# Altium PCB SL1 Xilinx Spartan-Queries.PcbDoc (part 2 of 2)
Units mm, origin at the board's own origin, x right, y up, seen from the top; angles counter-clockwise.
Board outline 180.01 x 50.51 mm, 2 copper layers (Top Layer, Bottom Layer), stack 1.646 mm thick; 115 components, 126 nets, 642 pads, 244 vias.
Unrouted connection lines stored in the file: 1.

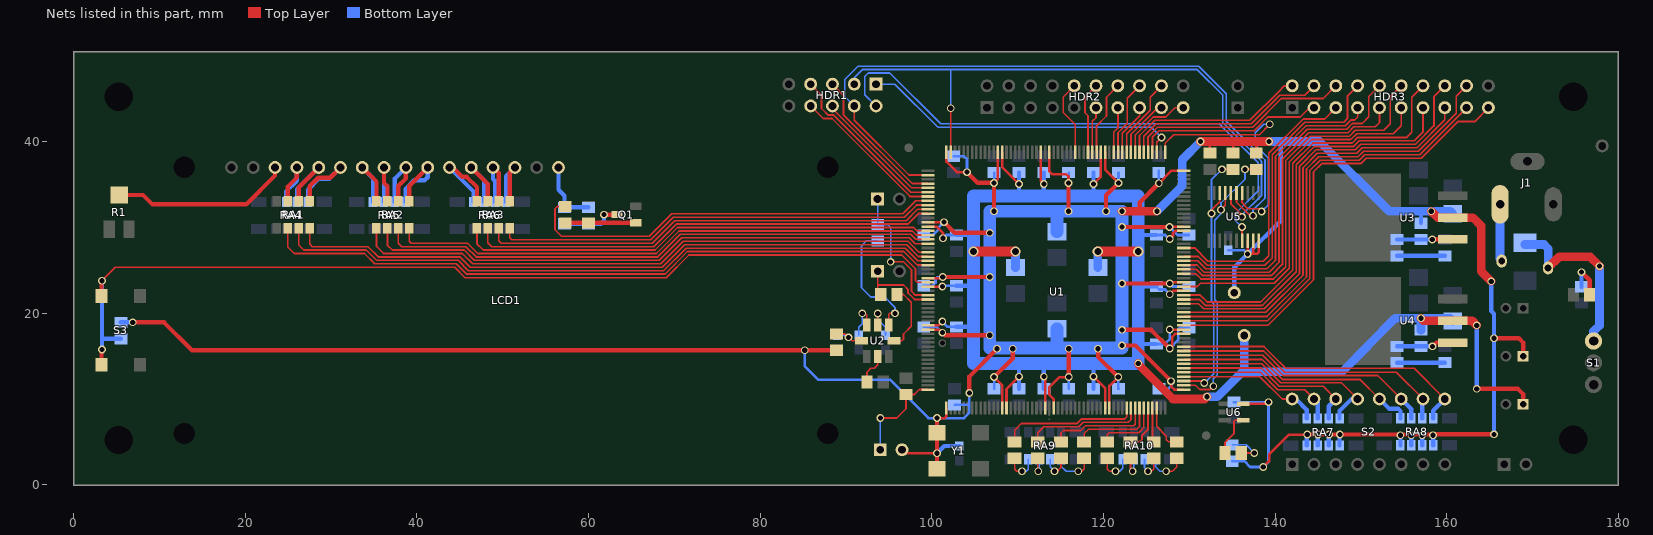
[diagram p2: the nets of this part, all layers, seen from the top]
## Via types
v1: diameter 0.9, hole 0.6, Top Layer to Bottom Layer, tented both sides, 168 vias
v2: diameter 1.5, hole 0.8, Top Layer to Bottom Layer, tented both sides, 46 vias
v3: diameter 1.2, hole 0.8, Top Layer to Bottom Layer, 18 vias
v4: diameter 1.2, hole 0.8, Top Layer to Bottom Layer, tented both sides, 11 vias
v5: diameter 0.9, hole 0.6, Top Layer to Bottom Layer, 1 vias

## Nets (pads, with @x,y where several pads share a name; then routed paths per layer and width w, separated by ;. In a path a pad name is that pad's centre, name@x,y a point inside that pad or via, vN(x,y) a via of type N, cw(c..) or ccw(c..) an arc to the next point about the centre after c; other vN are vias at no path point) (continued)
HA10: HDR2.10 U1.178 | length 8.8
  Top Layer w0.2: HDR2.10@116.6,46.5 115.3,45.2 115.3,43.4 116.7,42 U1.178@116.7,38.775
HA11: HDR2.11 U1.174 | length 5.4
  Top Layer w0.2: U1.174@118.7,38.775 118.7,42.375 119.14,42.815 HDR2.11@119.14,43.96
HA12: HDR2.12 U1.175 | length 8.4
  Top Layer w0.2: U1.175@118.2,38.775 118.2,43.025 117.85,43.375 117.85,45.21 HDR2.12@119.14,46.5
HA13: HDR2.13 U1.169 | length 5.4
  Top Layer w0.2: U1.169@121.2,38.775 121.2,41.122 121.68,41.602 HDR2.13@121.68,43.96
HA14: HDR2.14 U1.173 | length 8.8
  Top Layer w0.2: U1.173@119.2,38.775 119.2,41.85 120.35,43 120.35,45.17 HDR2.14@121.68,46.5
HA15: HDR2.15 U1.167 | length 6
  Top Layer w0.2: U1.167@122.2,38.775 122.2,40.991 124.22,43.011 HDR2.15@124.22,43.96
HA16: HDR2.16 U1.168 | length 8.8
  Top Layer w0.2: U1.168@121.7,38.775 121.7,41.056 122.775,42.131 122.775,45.055 HDR2.16@124.22,46.5
HA17: HDR2.17 U1.165 | length 6.9
  Top Layer w0.2: U1.165@123.2,38.775 123.2,40.85 126.31,43.96 HDR2.17@126.76,43.96
HA18: HDR2.18 U1.166 | length 9.4
  Top Layer w0.2: U1.166@122.7,38.775 122.7,40.925 125.45,43.675 125.45,45.19 HDR2.18@126.76,46.5
HA19: HDR2.19 U1.164 | length 8.9
  Top Layer w0.2: U1.164@123.7,38.775 123.7,40.784 125.801,42.885 127.26,42.885 128.335,43.96 HDR2.19@129.3,43.96
HARD_TCK: HDR1.3 U1.207 U5.6 | length 75.3
  Top Layer w0.2: U1.207@102.2,38.775 v1(102.2,43.9) ; U5.6@134.85,34 134.85,32.769 136.144,31.475 v1(136.144,31.242)
  Bottom Layer w0.2: HDR1.3@90.96,46.7 90.96,47.46 91.9,48.4 130.934,48.4 133.9,45.434 133.9,42.225 ; v1(102.2,43.9) 102.2,48.4 ; 133.9,42.234 134.125,42.009 134.125,42 138.425,37.7 138.425,33.777 136.144,31.496 v1(136.144,31.242)
HARD_TDI: HDR1.1 U1.159 | length 37.8
  Top Layer w0.2: U1.159@126.2,38.775 126.2,39.95 v1(126.75,40.5)
  Bottom Layer w0.2: HDR1.1@93.5,46.7 95.7,46.7 100.725,41.675 125.575,41.675 v1(126.75,40.5)
HARD_TDO: HDR1.2 U5.17 | length 64.8
  Top Layer w0.2: U5.17@136.15,28.45 v1(136.15,30.05)
  Bottom Layer w0.2: HDR1.2@93.5,44.16 92.2,45.46 92.2,47.6 92.6,48 95.1,48 101.025,42.075 133.484,42.075 134.723,40.837 138.025,37.534 138.025,34.266 135.39,31.631 135.39,30.81 v1(136.15,30.05)
HARD_TMS: HDR1.4 U1.2 U5.5 | length 83.2
  Top Layer w0.2: HDR1.4@90.96,44.16 90.96,42.5 97.335,36.125 U1.2@99.55,36.125 ; U5.5@135.5,34 135.5,32.95 137.081,31.369 v1(137.414,31.369)
  Bottom Layer w0.2: HDR1.4@90.96,44.16 89.85,45.27 89.85,47.25 91.405,48.805 131.095,48.805 134.3,45.6 134.3,42.4 138.825,37.875 138.825,33.415 137.414,32.004 v1(137.414,31.369)
HB2: HDR3.2 U1.163 | length 22.1
  Top Layer w0.2: U1.163@124.2,38.775 124.2,40.719 125.967,42.485 137.054,42.485 140.402,45.833 141.069,46.5 HDR3.2@142,46.5
HB3: HDR3.3 U1.160 | length 22
  Top Layer w0.2: U1.160@125.7,38.775 125.7,40.522 126.464,41.285 137.551,41.285 139.149,42.883 142.933,42.883 144.01,43.96 HDR3.3@144.54,43.96
HB4: HDR3.4 U1.162 | length 24.1
  Top Layer w0.2: U1.162@124.7,38.775 124.7,40.653 126.132,42.085 137.22,42.085 140.559,45.425 143.465,45.425 HDR3.4@144.54,46.5
HB5: HDR3.5 U1.138 | length 32.8
  Top Layer w0.2: U1.138@129.35,27.625 130.616,27.625 132.162,26.079 138.629,26.079 139.25,26.7 139.25,38.634 143.266,42.65 145.77,42.65 HDR3.5@147.08,43.96
HB6: HDR3.6 U1.161 | length 26.1
  Top Layer w0.2: U1.161@125.2,38.775 125.2,40.587 126.298,41.685 137.385,41.685 140.725,45.025 145.605,45.025 HDR3.6@147.08,46.5
HB7: HDR3.7 U1.135 | length 36.2
  Top Layer w0.2: U1.135@129.35,26.125 130.984,26.125 131.909,25.2 139.05,25.2 140.05,26.2 140.05,38.303 143.597,41.85 148.166,41.85 148.825,42.509 148.825,42.525 149.275,42.525 149.62,42.87 HDR3.7@149.62,43.96
HB8: HDR3.8 U1.136 | length 37.9
  Top Layer w0.2: U1.136@129.35,26.625 131.05,26.625 132.075,25.6 138.8,25.6 139.65,26.45 139.65,38.469 143.431,42.25 148,42.25 148.425,42.675 148.425,45.305 HDR3.8@149.62,46.5
HB9: HDR3.9 U1.133 | length 39.4
  Top Layer w0.2: U1.133@129.35,25.125 130.825,25.125 131.55,24.4 139.55,24.4 140.85,25.7 140.85,34.825 140.85,37.972 143.928,41.05 148.497,41.05 149.172,41.725 151.675,41.725 152.16,42.21 HDR3.9@152.16,43.96
HB10: HDR3.10 U1.134 | length 40.7
  Top Layer w0.2: U1.134@129.35,25.625 130.891,25.625 131.716,24.8 139.3,24.8 140.45,25.95 140.45,38.137 143.763,41.45 148.331,41.45 149.006,42.125 150.15,42.125 150.925,42.9 150.925,45.265 HDR3.10@152.16,46.5
HB11: HDR3.11 U1.129 | length 42.5
  Top Layer w0.2: U1.129@129.35,23.125 130.925,23.125 131.305,23.505 139.905,23.505 141.65,25.25 141.65,35.4 141.65,37.64 144.26,40.25 148.828,40.25 149.503,40.925 153.75,40.925 154.7,41.875 HDR3.11@154.7,43.96
HB12: HDR3.12 U1.132 | length 44
  Top Layer w0.2: U1.132@129.35,24.625 130.75,24.625 131.375,24 139.8,24 141.25,25.45 141.25,37.806 144.094,40.65 148.663,40.65 149.338,41.325 152.675,41.325 153.425,42.075 153.425,45.225 HDR3.12@154.7,46.5
HB13: HDR3.13 U1.126 | length 46.7
  Top Layer w0.2: U1.126@129.35,21.625 131.175,21.625 131.875,20.925 138.525,20.925 142.45,24.85 142.45,35.175 142.45,37.309 144.591,39.45 149.16,39.45 149.81,40.1 156.197,40.1 157.24,41.143 HDR3.13@157.24,43.96
HB14: HDR3.14 U1.127 | length 48.3
  Top Layer w0.2: U1.127@129.35,22.125 131.275,22.125 132.075,21.325 138.325,21.325 142.05,25.05 142.05,35.2 142.05,37.475 144.425,39.85 148.994,39.85 149.644,40.5 155.325,40.5 155.925,41.1 155.925,45.185 HDR3.14@157.24,46.5
HB15: HDR3.15 U1.123 | length 48.5
  Top Layer w0.2: U1.123@129.35,20.125 138.925,20.125 143.25,24.45 143.25,36.977 144.923,38.65 149.491,38.65 150.141,39.3 156.529,39.3 159.78,42.551 HDR3.15@159.78,43.96
HB16: HDR3.16 U1.125 | length 50.7
  Top Layer w0.2: U1.125@129.35,21.125 131.075,21.125 131.675,20.525 138.725,20.525 142.85,24.65 142.85,34.7 142.85,37.143 144.757,39.05 149.325,39.05 149.975,39.7 156.363,39.7 158.5,41.837 158.5,45.22 HDR3.16@159.78,46.5
HB17: HDR3.17 U1.121 | length 50.6
  Top Layer w0.2: U1.121@129.35,19.125 139.109,19.125 144.05,24.066 144.05,36.646 145.254,37.85 149.823,37.85 150.448,38.475 156.835,38.475 HDR3.17@162.32,43.96
HB18: HDR3.18 U1.122 | length 52.6
  Top Layer w0.2: U1.122@129.35,19.625 139.044,19.625 143.65,24.231 143.65,36.812 145.088,38.25 149.657,38.25 150.307,38.9 156.694,38.9 161.1,43.306 161.1,45.28 HDR3.18@162.32,46.5
HB19: HDR3.19 U1.120 | length 53.4
  Top Layer w0.2: U1.120@129.35,18.625 139.175,18.625 144.475,23.925 144.475,36.505 145.42,37.45 149.988,37.45 150.613,38.075 157.025,38.075 161.291,42.341 163.241,42.341 HDR3.19@164.86,43.96
I\N\I\T\: R5.2 U1.107 U5.8 | length 32.6
  Top Layer w0.2: U1.107@129.35,12.125 131.5,12.125 v1(131.75,11.875) ; v1(132.575,31.625) 132.575,32.025 133.55,33 U5.8@133.55,34 ; v1(133.803,36.78) R5.2@135.1,36.775
  Bottom Layer w0.2: v1(131.75,11.875) 132.85,12.975 132.85,21.132 132.575,21.407 132.575,35.552 v1(133.803,36.78)
JTAG_NEXUS_TCK: HDR1.7 U1.6 | length 19.8
  Top Layer w0.2: HDR1.7@85.88,46.7 87.15,45.43 87.15,43.875 87.925,43.1 88.575,43.1 97.55,34.125 U1.6@99.55,34.125
JTAG_NEXUS_TDI: HDR1.5 U1.4 | length 17.3
  Top Layer w0.2: HDR1.5@88.42,46.7 89.7,45.42 89.7,43.15 97.725,35.125 U1.4@99.55,35.125
JTAG_NEXUS_TDO: HDR1.6 U1.5 | length 15.3
  Top Layer w0.2: HDR1.6@88.42,44.16 88.42,43.83 97.625,34.625 U1.5@99.55,34.625
JTAG_NEXUS_TMS: HDR1.8 U1.7 | length 18
  Top Layer w0.2: HDR1.8@85.88,44.16 87.34,42.7 88.375,42.7 97.45,33.625 U1.7@99.55,33.625
LCD_CONTRAST: LCD1.3 R1.W | length 21
  Top Layer w0.5: R1.W@5.3,33.8 8.1,33.8 9.2,32.7 20.113,32.7 23.48,36.067 LCD1.3@23.48,37
LCD_DB0: RA2.5 U1.20 | length 68.8
  Top Layer w0.2: RA2.5@35.295,29.925 35.295,27.8 36.12,26.975 45.3,26.975 46.5,25.775 68.41,25.775 71.035,28.4 97.225,28.4 98.5,27.125 U1.20@99.55,27.125
LCD_DB1: RA2.6 U1.18 | length 67.1
  Top Layer w0.2: RA2.6@36.565,29.925 36.565,27.935 37.125,27.375 45.5,27.375 46.7,26.175 68.244,26.175 70.869,28.8 97.391,28.8 98.066,28.125 U1.18@99.55,28.125
LCD_DB2: RA2.7 U1.17 | length 65.5
  Top Layer w0.2: RA2.7@37.835,29.925 37.835,28.165 38.225,27.775 45.7,27.775 46.9,26.575 68.078,26.575 70.703,29.2 97.556,29.2 98.131,28.625 U1.17@99.55,28.625
LCD_DB3: RA2.8 U1.16 | length 63.8
  Top Layer w0.2: RA2.8@39.105,29.925 39.105,28.395 39.325,28.175 45.9,28.175 47.1,26.975 67.913,26.975 70.538,29.6 97.722,29.6 98.197,29.125 U1.16@99.55,29.125
LCD_DB4: RA3.5 U1.15 | length 55.9
  Top Layer w0.2: RA3.5@46.995,29.925 46.995,28.105 47.725,27.375 67.747,27.375 70.372,30 97.888,30 98.263,29.625 U1.15@99.55,29.625
LCD_DB5: RA3.6 U1.11 | length 54.8
  Top Layer w0.2: RA3.6@48.265,29.925 48.265,28.235 48.725,27.775 67.581,27.775 70.206,30.4 97.197,30.4 98.422,31.625 U1.11@99.55,31.625
LCD_DB6: RA3.7 U1.10 | length 53.2
  Top Layer w0.2: RA3.7@49.535,29.925 49.535,28.465 49.825,28.175 67.416,28.175 70.041,30.8 97,30.8 98.325,32.125 U1.10@99.55,32.125
LCD_DB7: RA3.8 U1.9 | length 51.6
  Top Layer w0.2: RA3.8@50.805,29.925 50.805,28.82 51.05,28.575 67.25,28.575 69.875,31.2 96.8,31.2 98.225,32.625 U1.9@99.55,32.625
LCD_DB#0: LCD1.7 RA2.4 RA5.5 | length 9.2
  Top Layer w0.5: LCD1.7@33.64,37 35.295,35.345 RA2.4@35.295,33.075
  Bottom Layer w0.5: LCD1.7@33.64,37 34.895,35.745 RA5.5@34.895,32.975
LCD_DB#1: LCD1.8 RA2.3 RA5.6 | length 8.1
  Top Layer w0.5: LCD1.8@36.18,37 36.18,35.2 36.565,34.815 RA2.3@36.565,33.075
  Bottom Layer w0.5: RA5.6@36.165,32.975 36.165,36.985 LCD1.8@36.18,37
LCD_DB#2: LCD1.9 RA2.2 RA5.7 | length 8.8
  Top Layer w0.5: RA2.2@37.835,33.075 37.835,34.825 38.72,35.71 LCD1.9@38.72,37
  Bottom Layer w0.5: RA5.7@37.435,32.975 37.435,35.715 LCD1.9@38.72,37
LCD_DB#3: LCD1.10 RA2.1 RA5.8 | length 10.6
  Top Layer w0.5: RA2.1@39.105,33.075 39.105,34.845 LCD1.10@41.26,37
  Bottom Layer w0.5: RA5.8@38.705,32.975 38.705,34.505 39.7,35.5 40.9,35.5 41.26,35.86 LCD1.10@41.26,37
LCD_DB#4: LCD1.11 RA3.4 RA6.5 | length 11
  Top Layer w0.5: LCD1.11@43.8,37 44.2,37 45.297,35.903 45.797,35.903 46.995,34.705 RA3.4@46.995,33.075
  Bottom Layer w0.5: LCD1.11@43.8,37 46.595,34.205 RA6.5@46.595,32.975
LCD_DB#5: LCD1.12 RA3.3 RA6.6 | length 9.4
  Top Layer w0.5: LCD1.12@46.34,37 48.265,35.075 RA3.3@48.265,33.075
  Bottom Layer w0.5: LCD1.12@46.34,37 47.865,35.475 RA6.6@47.865,32.975
LCD_DB#6: LCD1.13 RA3.2 RA6.7 | length 8.3
  Top Layer w0.5: LCD1.13@48.88,37 49.535,36.345 RA3.2@49.535,33.075
  Bottom Layer w0.5: LCD1.13@48.88,37 48.88,35.655 49.135,35.4 RA6.7@49.135,32.975
LCD_DB#7: LCD1.14 RA3.1 RA6.8 | length 8.6
  Top Layer w0.5: RA3.1@50.805,33.075 50.805,36.385 LCD1.14@51.42,37
  Bottom Layer w0.5: RA6.8@50.405,32.975 50.405,35.985 LCD1.14@51.42,37
LCD_E: RA1.8 U1.21 | length 76.7
  Top Layer w0.2: RA1.8@27.505,29.925 27.505,28.095 27.825,27.775 34.3,27.775 35.5,26.575 45,26.575 46.2,25.375 68.575,25.375 71.2,28 97.059,28 98.434,26.625 U1.21@99.55,26.625
LCD_E#: LCD1.6 RA1.1 RA4.8 | length 12.5
  Top Layer w0.5: RA1.1@27.505,33.075 27.505,34.805 28.5,35.8 29.9,35.8 LCD1.6@31.1,37
  Bottom Layer w0.5: RA4.8@27.305,32.975 27.305,34.405 28.595,35.695 29.795,35.695 LCD1.6@31.1,37
LCD_LIGHT: R2.1 U1.8 | length 49.2
  Top Layer w0.2: R2.1@57.3,32.45 56.375,32.45 56.1,32.175 56.1,29.725 56.85,28.975 67.084,28.975 69.709,31.6 96.6,31.6 98.125,33.125 U1.8@99.55,33.125
LCD_RS: RA1.6 U1.23 | length 79.8
  Top Layer w0.2: RA1.6@24.965,29.925 24.965,27.735 25.725,26.975 33.9,26.975 35.1,25.775 44.6,25.775 45.8,24.575 68.907,24.575 71.532,27.2 96.725,27.2 98.3,25.625 U1.23@99.55,25.625
LCD_RS#: LCD1.4 RA1.3 RA4.6 | length 8.9
  Top Layer w0.5: RA1.3@24.965,33.075 24.965,34.79 26.02,35.845 LCD1.4@26.02,37
  Bottom Layer w0.5: RA4.6@24.765,32.975 24.765,34.195 26.02,35.45 LCD1.4@26.02,37
LCD_RW: RA1.7 U1.22 | length 78.2
  Top Layer w0.2: RA1.7@26.235,29.925 26.235,27.965 26.825,27.375 34.1,27.375 35.3,26.175 44.8,26.175 46,24.975 68.741,24.975 71.366,27.6 96.894,27.6 98.369,26.125 U1.22@99.55,26.125
LCD_RW#: LCD1.5 RA1.2 RA4.7 | length 10
  Top Layer w0.5: RA1.2@26.235,33.075 26.235,34.675 LCD1.5@28.56,37
  Bottom Layer w0.5: RA4.7@26.035,32.975 26.035,34.475 LCD1.5@28.56,37
LEDS0: LED0.1 U1.102 | length 5.5
  Top Layer w0.2: U1.102@126.2,8.975 126.2,6.825 127.325,5.7 127.325,5.275 127.575,5.025 LED0.1@128.55,5.025
LEDS1: LED1.1 U1.101 | length 4
  Top Layer w0.2: U1.101@125.7,8.975 125.7,8.875 125.7,5.175 LED1.1@125.85,5.025
LEDS2: LED2.1 U1.100 | length 5.4
  Top Layer w0.2: LED2.1@123.15,5.025 124.175,5.025 124.5,5.35 124.5,5.775 125.2,6.475 U1.100@125.2,8.975
LEDS3: LED3.1 U1.99 | length 7.7
  Top Layer w0.2: LED3.1@120.45,5.025 120.45,5.875 120.675,6.1 124.1,6.1 124.7,6.7 U1.99@124.7,8.975
LEDS4: LED4.1 U1.98 | length 9.9
  Top Layer w0.2: LED4.1@117.75,5.025 117.75,6 118.25,6.5 123.9,6.5 124.2,6.8 U1.98@124.2,8.975
LEDS5: LED5.1 U1.97 | length 12
  Top Layer w0.2: LED5.1@115.05,5.025 115.05,6.05 115.35,6.35 117.35,6.35 117.9,6.9 123.525,6.9 123.7,7.075 U1.97@123.7,8.975
LEDS6: LED6.1 U1.96 | length 13.9
  Top Layer w0.2: LED6.1@112.35,5.025 112.35,6.075 113.05,6.775 117.125,6.775 117.65,7.3 122.9,7.3 123.2,7.6 U1.96@123.2,8.975
LEDS7: LED7.1 U1.95 | length 16.1
  Top Layer w0.2: LED7.1@109.65,5.025 109.65,6.375 110.45,7.175 116.959,7.175 117.484,7.7 122.475,7.7 122.7,7.925 U1.95@122.7,8.975
M0: JP5.1 R7.2 U1.52 | length 11.6
  Top Layer w0.2: v1(94,7.8) 95.9,7.8 96.989,8.889 96.989,10.555 97.98,10.555 98.55,11.125 U1.52@99.55,11.125
  Bottom Layer w0.2: JP5.1@94,4.1 v1(94,7.8)
NetC15_1: C15.1 R11.2 U2.8 | length 4.6
  Top Layer w0.2: R11.2@88.88,17.6 89.9,17.6 90.7,16.8 U2.8@91.8,16.8
  Bottom Layer w0.2: C15.1@89,17.45 89.78,17.45 v1(90.3,17.2)
NetC16_1: C16.1 U2.6 | length 4.2
  Top Layer w0.2: U2.6@93.697,18.663 93.702,18.668 v1(93.702,19.988)
  Bottom Layer w0.2: v1(93.702,19.988) 93.702,19.28 94.6,18.383 C16.1@94.6,17.45
NetC19_1: C19.1 U2.7 | length 4.5
  Top Layer w0.2: v1(91.9,20) 92.2,20 92.43,19.77 U2.7@92.43,18.65
  Bottom Layer w0.2: C19.1@91.5,17.45 91.5,18.392 91.9,18.792 v1(91.9,20)
NetD1_2: D1.2 F1.2 S1.3 | length 21.2
  Top Layer w1: F1.2@171.8,25.3 173.1,26.6 176.7,26.6 v1(177.8,25.5)
  Bottom Layer w1: D1.2@169.1,28.022 171.325,28.025 171.8,27.55 F1.2@171.8,25.3 ; S1.3@177.1,16.78 177.1,17.9 177.8,18.58 v1(177.8,25.5)
NetLCD1_16: LCD1.16 R8.1 R9.1 | length 7.7
  Bottom Layer w0.5: LCD1.16@56.5,37 56.5,34.4 57.2,33.7 57.2,32.35 R9.1@60,32.35
NetLED0_2: LED0.2 RA10.5 | length 5.5
  Top Layer w0.2: v1(127.3,1.6) 128.05,1.6 128.55,2.1 LED0.2@128.55,3.125
  Bottom Layer w0.2: RA10.5@126.055,3 126.055,2.125 126.58,1.6 ; 126.58,1.6 v1(127.3,1.6) 126.58,1.6
NetLED1_2: LED1.2 RA10.6 | length 3.6
  Top Layer w0.2: v1(125.2,1.6) 125.6,1.6 125.85,1.85 LED1.2@125.85,3.125
  Bottom Layer w0.2: RA10.6@124.785,3 124.785,2.015 v1(125.2,1.6)
NetLED2_2: LED2.2 RA10.7 | length 3.1
  Top Layer w0.2: LED2.2@123.15,3.125 123.15,1.85 v1(123.4,1.6)
  Bottom Layer w0.2: v1(123.4,1.6) 123.515,1.715 RA10.7@123.515,3
NetLED3_2: LED3.2 RA10.8 | length 4.4
  Top Layer w0.2: LED3.2@120.45,3.125 120.45,1.85 120.7,1.6 v1(121.4,1.6)
  Bottom Layer w0.2: v1(121.4,1.6) 121.9,1.6 122.245,1.945 RA10.8@122.245,3
NetLED4_2: LED4.2 RA9.5 | length 5.1
  Top Layer w0.2: v1(117.055,1.6) 117.45,1.6 117.75,1.9 LED4.2@117.75,3.125
  Bottom Layer w0.2: RA9.5@115.055,3 115.055,2.2 115.655,1.6 v1(117.055,1.6)
NetLED5_2: LED5.2 RA9.6 | length 3.6
  Top Layer w0.2: v1(114.3,1.6) 114.6,1.6 115.05,2.05 LED5.2@115.05,3.125
  Bottom Layer w0.2: RA9.6@113.785,3 113.785,2.115 v1(114.3,1.6)
NetLED6_2: LED6.2 RA9.7 | length 3
  Top Layer w0.2: LED6.2@112.35,3.125 112.35,1.65 v1(112.4,1.6)
  Bottom Layer w0.2: v1(112.4,1.6) 112.515,1.715 RA9.7@112.515,3
NetLED7_2: LED7.2 RA9.8 | length 4.2
  Top Layer w0.2: LED7.2@109.65,3.125 109.65,1.85 109.9,1.6 v1(110.5,1.6)
  Bottom Layer w0.2: v1(110.5,1.6) 111,1.6 111.245,1.845 RA9.8@111.245,3
NetLED8_1: LED8.1 R20.1 | length 4.5
  Top Layer w0.2: LED8.1@136.05,3.725 v1(137.575,3.725)
  Bottom Layer w0.2: R20.1@135,4.675 136.625,4.675 v1(137.575,3.725)
NetLED8_2: LED8.2 U6.4 | length 5.2
  Top Layer w0.2: LED8.2@134.15,3.725 134.15,4.925 135.2,5.975 135.2,7.4 135.35,7.55 U6.4@136.275,7.55
NetLED9_1: LED9.1 R15.1 | length 4.7
  Top Layer w0.5: v1(175.7,24.8) 176.65,23.85 LED9.1@176.65,22.15
  Bottom Layer w0.5: R15.1@175.7,23.1 v1(175.7,24.8)
NetQ1_1: Q1.1 R2.2 R3.2 | length 8.2
  Top Layer w0.5: R2.2@57.3,30.55 Q1.1@65.5,30.55
NetQ1_3: Q1.3 R8.2 R9.2 | length 6.9
  Top Layer w0.5: v1(61.8,31.5) Q1.3@63.3,31.5
  Bottom Layer w0.5: R8.2@57.2,30.45 61.45,30.45 61.8,30.8 v1(61.8,31.5)
NetR10_2: R10.2 U2.2 | length 3.7
  Top Layer w0.2: R10.2@92.45,12 92.45,13.15 92.9,13.6 93.28,13.6 93.7,14.02 U2.2@93.7,14.95
NetR12_1: R12.1 R13.2 U3.1 | length 6.5
  Top Layer w0.5: v1@158.32,28.62 U3.1@160.7,28.62
  Bottom Layer w0.5: R12.1@154.2,28.6 157,28.6 v1(158.3,28.6)
NetR12_2: R12.2 R14.2 | length 5.6
  Bottom Layer w0.5: R12.2@154.2,26.7 R14.2@159.8,26.7
NetR17_1: R17.1 R18.2 U4.1 | length 6.7
  Top Layer w0.5: v1(158.35,16.15) 158.8,16.6 U4.1@160.7,16.6
  Bottom Layer w0.5: R17.1@154.2,16.15 v1(158.35,16.15)
NetR17_2: R17.2 R19.1 | length 5.6
  Bottom Layer w0.5: R17.2@154.2,14.25 R19.1@159.8,14.25
PROG_B: R6.2 U1.106 U5.7 | length 34.3
  Top Layer w0.2: U1.106@129.35,11.625 130.725,11.625 131.225,11.125 132.425,11.125 v1(132.8,11.5) ; v1(133.7,32.075) 134.2,32.575 U5.7@134.2,34 ; v1(136.5,36.775) R6.2@137.8,36.775
  Bottom Layer w0.2: v1(132.8,11.5) 132.8,12.359 133.25,12.809 133.25,21.297 132.975,21.572 132.975,30.867 133.7,31.592 133.7,32.85 136.5,35.65 v1(136.5,36.775)
PWR_IN: F1.1 J1.1 | length 7.9
  Bottom Layer w1: J1.1@166.2,33.95 166.2,26.35 F1.1@166.4,26.1
SW0: RA7.1 S2.16 U1.108 | length 17.8
  Top Layer w0.2: U1.108@129.35,12.625 138.225,12.625 140.83,10.02 S2.16@142,10.02
  Bottom Layer w0.5: S2.16@142,10.02 142.43,10.02 143.695,8.755 143.695,7.755 143.7,7.75 143.7,8.63
SW1: RA7.2 S2.15 U1.109 | length 20.6
  Top Layer w0.2: U1.109@129.35,13.125 138.3,13.125 140.325,11.1 143.46,11.1 S2.15@144.54,10.02
  Bottom Layer w0.5: S2.15@144.54,10.02 144.97,9.59 RA7.2@144.97,7.75 ; RA7.2@144.965,7.875 S2.15@144.965,9.595
SW2: RA7.3 S2.14 U1.110 | length 21.8
  Top Layer w0.2: U1.110@129.35,13.625 138.375,13.625 140.5,11.5 145.6,11.5 S2.14@147.08,10.02
  Bottom Layer w0.5: RA7.3@146.24,7.75 146.24,9.18 S2.14@147.08,10.02
SW3: RA7.4 S2.13 U1.111 | length 25.5
  Top Layer w0.2: U1.111@129.35,14.125 138.441,14.125 140.666,11.9 147.74,11.9 S2.13@149.62,10.02
  Bottom Layer w0.5: RA7.4@147.51,7.75 147.51,8.635 148.895,10.02 S2.13@149.62,10.02
SW4: RA8.1 S2.12 U1.112 | length 28.6
  Top Layer w0.2: U1.112@129.35,14.625 138.506,14.625 139.447,13.685 140.831,12.3 149.88,12.3 152.16,10.02 S2.12@152.13,10.02
  Bottom Layer w0.5: S2.12@152.16,10.02 153.309,8.871 154.346,8.871 154.6,8.617 RA8.1@154.6,7.75
SW5: RA8.2 S2.11 U1.113 | length 30.2
  Top Layer w0.2: U1.113@129.35,15.125 138.572,15.125 139.506,14.191 140.947,12.75 151.97,12.75 S2.11@154.7,10.02
  Bottom Layer w0.5: S2.11@154.7,10.02 155.87,8.85 RA8.2@155.87,7.75
SW6: RA8.3 S2.10 U1.114 | length 32.5
  Top Layer w0.2: U1.114@129.35,15.625 138.638,15.625 141.113,13.15 154.11,13.15 S2.10@157.24,10.02
  Bottom Layer w0.5: RA8.3@157.14,7.75 157.14,9.92 S2.10@157.24,10.02
SW7: RA8.4 S2.9 U1.115 | length 35.8
  Top Layer w0.2: U1.115@129.35,16.125 138.703,16.125 139.695,15.133 141.228,13.6 156.2,13.6 S2.9@159.78,10.02
  Bottom Layer w0.5: RA8.4@158.41,7.75 158.41,8.65 S2.9@159.78,10.02
TDI_C: U1.157 U5.4 | length 30.2
  Top Layer w0.2: U1.157@127.2,38.775 127.2,39.85 128.175,40.825 138.175,40.825 v1(139.375,42.025) ; U5.4@136.15,34 136.15,32.875 136.825,32.2 138.107,32.2 v1(138.43,31.877)
  Bottom Layer w0.2: v1(138.43,31.877) 139.225,32.672 139.225,38.065 137.7,39.59 137.7,41.05 138.675,42.025 v1(139.375,42.025)
TEST: R16.2 S3.1 S3.2 U1.27 | length 114.4
  Top Layer w0.2: v1(3.3,23.8) 4.865,25.365 44.4,25.365 45.615,24.15 69.05,24.15 71.7,26.8 96.5,26.8 98.1,25.2 98.1,23.825 98.3,23.625 U1.27@99.55,23.625
  Top Layer w0.5: S3.1@3.25,13.99 3.25,15.75 v1(3.3,15.8) ; S3.2@3.25,22 v1@3.25,23.75
  Bottom Layer w0.5: v1(3.3,15.8) v1(3.3,23.8) ; 3.3,17.05 R16.2@5.5,17.05
VCCINT: C3.1 C7.1 C8.1 C10.1 C20.1 C21.1 C25.1 C26.1 C28.1 C29.1 C30.1 C32.1 C34.2 C38.1 C39.1 C41.1 R18.1 TP3.1 U1.14 U1.28 U1.37 U1.67 U1.76 U1.90 U1.119 U1.128 U1.142 U1.172 U1.186 U1.195 U4.2 | length 236.6
  Top Layer w0.3: U1.37@99.548,18.613 100.788,18.613 v1(101.225,19.05) ; U1.28@99.548,23.113 v1@101.225,23.113 ; U1.14@99.548,30.113 100.537,30.113 101.3,29.35 v1(101.3,28.75) ; U1.195@108.198,38.763 108.198,37.027 v1(110.15,35.075) ; U1.67@108.698,8.963 108.698,11.173 v1(110.15,12.625) ; U1.186@112.698,38.763 112.698,35.427 v1(113.05,35.075) ; v1(113.05,12.625) 113.198,12.477 U1.76@113.198,8.963 ; v1(118.85,12.625) 120.198,11.277 U1.90@120.198,8.963 ; v1(118.85,35.075) 119.698,35.923 U1.172@119.698,38.763 ; v1@127.725,18.113 U1.119@129.348,18.113 ; v1(127.725,22.225) 128.113,22.613 U1.128@129.348,22.613 ; v1(127.725,28.65) 128.1,29.025 128.1,29.318 128.395,29.613 U1.142@129.348,29.613
  Top Layer w0.5: v1(163.5,11.2) 168.3,11.2 168.9,10.6 C3.1@168.9,9.4
  Top Layer w1: v1(124.05,14.175) 124.15,13.975 128.106,10.019 131.819,10.019 v1(132.075,10.275) ; v1(157,19.425) 157.285,19.14 162.96,19.14 v1(163.5,18.6)
  Top Layer w1.2: v4(104.85,27.2) v4(109.75,27.2) ; v4(119.35,27.2) v4(124.05,27.2)
  Bottom Layer w0.3: v1(101.225,19.05) 101.85,18.425 C32.1@102.85,18.425 ; v1(101.225,23.125) 101.225,23.225 C25.1@102.85,23.225 ; v1(101.3,28.75) 101.675,29.125 C20.1@102.85,29.125 ; C34.2@126.15,16.425 127.121,16.425 ; C26.1@126.15,23.125 126.5,22.775 127.175,22.775 v1(127.725,22.225) ; C21.1@126.15,29.125 127.175,29.125 127.65,28.65 v1(127.725,28.65) ; 127.111,16.436 127.21,16.535 ; 127.222,16.522 127.725,17.025 v1(127.725,18.125)
  Bottom Layer w0.5: C32.1@102.85,18.425 104.85,18.425 ; C25.1@102.85,23.225 104.85,23.225 ; C20.1@102.85,29.125 104.85,29.125 ; C38.1@110.15,11.225 v1(110.15,12.625) 110.15,13.975 ; 110.15,33.8 v1(110.15,35.075) C7.1@110.15,36.4 ; C39.1@113.05,11.225 113.05,13.975 ; 113.05,33.8 C8.1@113.05,36.4 ; C41.1@118.85,11.225 118.85,13.975 ; 118.85,33.8 C10.1@118.85,36.4 ; 124.05,16.425 C34.2@126.15,16.425 ; 124.05,23.125 C26.1@126.15,23.125 ; 124.05,29.125 C21.1@126.15,29.125 ; v1(163.5,11.2) v1(163.5,18.6)
  Bottom Layer w1: C28.1@109.75,25.325 v4(109.75,27.2) ; C29.1@119.35,25.325 v4(119.35,27.2) ; v1(132.075,10.275) 133.275,10.275 136.175,13.175 147.8,13.175 153.975,19.425 160.375,19.425 C30.1@160.7,19.1 ; 136.4,13.175 TP3.1@136.4,17.4 ; R18.1@157,18.05 v1(157,19.425)
  Bottom Layer w1.5: 104.85,14.175 v4(104.85,27.2) 104.85,33.675 118.85,33.675 124.05,33.675 v1(124.05,14.175) 104.85,14.175
VCCO: C2.1 C4.1 C5.2 C6.1 C9.1 C11.1 C12.1 C14.1 C17.2 C18.2 C22.2 C23.1 C24.2 C31.1 C33.1 C35.1 C36.2 C37.1 C40.1 C42.1 C43.1 C44.2 C45.1 JP5.2 R4.1 R5.1 R6.1 R11.1 R13.1 R16.1 R20.2 RA7.5 RA7.6 RA7.7 RA7.8 RA8.5 RA8.6 RA8.7 RA8.8 TP2.1 U1.13 U1.26 U1.38 U1.53 U1.66 U1.78 U1.91 U1.105 U1.118 U1.130 U1.143 U1.156 U1.171 U1.184 U1.196 U1.208 U3.2 U5.18 U5.19 U5.20 U6.5 Y1.1 Y1.4 | length 536.7
  Top Layer w0.3: JP5.2@96.54,4.1 96.94,3.7 v1(100.6,3.7) ; U1.38@99.548,18.113 100.862,18.113 v1@101.525,17.45 ; U1.26@99.548,24.113 101.163,24.113 v1(101.275,24.225) v1@101.4,24.225 ; U1.13@99.548,30.613 v1@101.425,30.613 ; v1(100.6,7.8) 101.5,7.8 101.698,7.998 U1.53@101.698,8.963 ; U1.208@101.698,38.763 101.698,37.677 102.925,36.45 v1(104.1,36.45) ; v1(107.25,12.575) 108.198,11.627 U1.66@108.198,8.963 ; v1(107.25,35.2) 107.698,35.648 U1.196@107.698,38.763 ; U1.184@113.698,38.763 113.698,36.552 114.025,36.225 115.65,36.225 115.925,35.95 v1(115.925,35.2) ; U1.78@114.198,8.963 114.198,10.002 113.7,10.5 113.7,11.4 114.875,12.575 v1(115.95,12.575) ; U1.171@120.198,38.763 120.198,36.752 v1(121.75,35.2) ; U1.91@120.698,8.963 120.698,11.548 v1(121.725,12.575) ; v1(126.45,35.15) 127.925,36.625 U1.156@129.35,36.625 ; v1(127.7,30.05) 127.7,30.113 U1.143@129.348,30.113 ; v1(127.725,15.9) 128.017,16.192 128.017,17.273 128.357,17.613 U1.118@129.348,17.613 ; v1(127.725,23.475) v1@127.875,23.625 ; v1(127.875,12.1) 127.875,11.5 128.262,11.113 U1.105@129.348,11.113 ; v1@127.887,23.613 U1.130@129.348,23.613 ; R4.1@132.4,38.675 132.4,39.85 ; R5.1@135.1,38.675 135.1,39.85 ; U6.5@136.275,9.45 139.025,9.45 v1(139.225,9.65) ; U5.18@136.8,28.45 v1(136.8,26.925) 137.9,26.925 138.1,27.125 U5.20@138.1,28.45 ; 137.45,26.925 U5.19@137.45,28.45 ; R6.1@137.8,38.675 137.8,40.075 137.825,40.1 ; v1(138.625,2.1) 139.298,2.773 139.298,3.558 141.615,5.875 v1(143.735,5.875)
  Top Layer w0.5: v1(6.9,18.95) 10.55,18.95 13.8,15.7 v1(85.2,15.7) R11.1@88.88,15.7 ; Y1.1@100.6,1.6 v1(100.6,7.8) ; v1(101.275,24.225) v1(106.75,24.225) ; v1(101.425,30.625) 102.675,29.375 v1(106.75,29.375) ; v1@101.525,17.45 v1(106.75,17.45) ; v1(104.1,36.45) 105.35,35.2 v1(107.25,35.2) v1(107.25,31.9) ; v1(104.375,10.725) 104.375,12.65 v1(107.6,15.875) ; v1(107.25,12.575) 109.425,14.75 v1(109.425,15.875) ; v1(115.925,31.9) v1(115.925,35.2) ; v1(115.95,12.575) v1(115.95,15.875) ; v1(119.375,15.875) 119.375,14.925 v1(121.725,12.575) ; v1(120.3,31.9) 120.3,33.75 v1(121.75,35.2) ; v1(122.15,16.25) 123.725,16.25 v1(127.875,12.1) ; v1(122.15,18.075) 125.55,18.075 v1(127.725,15.9) ; v1(122.15,23.475) v1(127.725,23.475) ; v1(122.15,30.05) v1(127.7,30.05) ; 124.225,31.9 124.225,32.925 v1(126.45,35.15) ; v1(131.3,40.025) 131.55,39.85 137.55,39.85 ; v1(143.735,5.875) v1@158.445,5.875 ; v1(158.4,5.8) 158.5,5.9 v1(165.5,5.9) ; v1(165.5,17.1) 168.4,17.1 168.9,16.6 C2.1@168.9,15
  Top Layer w1: v1(122.15,31.9) v1(126.225,31.9) ; v1(131.3,40.025) v1(139.3,40.025) ; v1(158.2,31.9) 158.94,31.16 163.04,31.16 164,30.2 164,24.9 v1(165.175,23.725)
  Bottom Layer w0.3: v1(85.2,15.7) 85.2,13.825 86.75,12.275 95.15,12.275 99.6,7.8 103.75,7.8 104.375,8.425 v1(104.375,10.725) ; C31.1@99.05,18.425 100.55,18.425 v1(101.225,17.75) ; C22.2@99.05,23.225 100.075,23.225 100.425,23.575 100.425,23.975 100.675,24.225 v1(101.275,24.225) ; C17.2@99.05,29.125 100.125,29.125 100.725,29.725 100.725,29.925 v1(101.425,30.625) ; C5.2@102.55,38.3 103.775,38.3 104.1,37.975 v1(104.1,36.45) ; C36.2@102.65,9.325 104.375,9.325 ; C37.1@107.25,11.225 v1(107.25,12.575) ; v1(107.25,35.2) C6.1@107.25,36.4 ; v1(115.925,35.2) C9.1@115.95,36.4 ; C40.1@115.95,11.225 v1(115.95,12.575) ; v1(121.725,12.575) 121.725,11.25 C42.1@121.75,11.225 ; v1(121.75,35.2) C11.1@121.75,36.4 ; C43.1@126.45,11.225 127.575,11.225 127.875,11.525 v1(127.875,12.1) ; v1(126.45,35.15) C12.1@126.45,36.625 ; v1(127.7,30.05) 128.625,29.125 C18.2@129.95,29.125 ; v1(127.725,15.9) 128.7,16.875 128.7,18.125 128.9,18.325 C35.1@129.95,18.325 ; v1(127.725,23.475) 128.075,23.125 C24.2@129.95,23.125 ; C4.1@134.525,27.35 136.375,27.35 v1(136.8,26.925) ; R20.2@135,2.775 136.425,2.775 137.1,2.1 v1(138.625,2.1) 139.225,2.7 v1(139.225,9.65) C44.2@135.2,9.65
  Bottom Layer w0.5: R16.1@5.5,18.95 v1(6.9,18.95) ; v1(100.6,3.7) 101.45,4.55 C45.1@103.2,4.55 ; TP2.1@135.233,22.4 135.233,25.358 v1(136.8,26.925) 140.65,30.75 140.65,40.025 v1(139.3,40.025) ; RA7.8@143.7,4.6 v1@143.7,5.84 ; RA7.7@144.97,4.6 v1@144.97,5.84 ; RA7.6@146.24,4.6 v1@146.24,5.84 ; RA7.5@147.51,4.6 v1@147.51,5.84 ; RA8.8@154.6,4.6 v1@154.6,5.84 ; RA8.7@155.87,4.6 v1@155.87,5.84 ; R13.1@157,30.55 157,31.925 ; RA8.6@157.14,4.6 v1@157.14,5.84 ; RA8.5@158.41,4.6 v1@158.41,5.84 ; v1(165.175,23.725) 165.175,20.275 165.5,19.95 v1(165.5,17.1) v1(165.5,5.9)
  Bottom Layer w1: v1(126.225,31.9) 129.175,34.85 129.175,37.9 v1(131.3,40.025) ; v1(139.3,40.025) 145.175,40.025 153.3,31.9 160.4,31.9 C14.1@160.7,31.6
  Bottom Layer w1.5: 114.6,16 C33.1@114.6,18.2 ; C23.1@114.6,29.5 114.6,31.9 ; 114.6,31.9 v1(107.25,31.9) 106.75,31.9 v1(106.75,24.225) v1(106.75,17.45) 106.75,15.975 122.15,15.975 v1(122.15,31.9) 114.6,31.9
  other v1: 154.59,5.8 155.86,5.8 157.13,5.8 145.005,5.875 146.275,5.875 147.545,5.875
XOUT: R22.2 U2.5 | length 15
  Top Layer w0.2: U2.5@94.97,18.65 94.97,19.57 94.97,19.87 95.1,20 v1(95.7,20)
  Bottom Layer w0.2: R22.2@93.711,28.455 92.355,28.455 91.8,27.8 91.8,23 92.9,21.9 94.514,21.9 95.7,20.714 v1(95.7,20) v1@95.4,20.3
XOUT_ALT: JP3.1 R22.1 U1.30 | length 16
  Top Layer w0.2: v1(95.2,26) 96.7,26 97.633,25.067 97.633,22.567 98.075,22.125 U1.30@99.55,22.125
  Bottom Layer w0.2: JP3.1@93.693,33.31 93.693,30.373 93.711,30.355 94.845,30.355 95.2,30 v1(95.2,26)
YOUT: R21.2 U2.4 | length 7.9
  Top Layer w0.2: U2.4@95.6,16.8 96.5,16.8 96.7,17 96.7,17.6 97.6,18.5 97.6,21.286 96.697,22.189 R21.2@95.945,22.189
YOUT_ALT: JP4.1 R21.1 U1.31 | length 9.6
  Top Layer w0.2: JP4.1@93.693,24.91 93.693,22.54 R21.1@94.045,22.189 ; 93.793,23.3 96.7,23.3 97.233,22.767 97.233,22.367 97.975,21.625 U1.31@99.55,21.625
pads on no net: HDR2.1 HDR3.1 LCD1.M1 LCD1.M2 LCD1.M3 LCD1.M4 RA1.4 RA1.5 RA4.5 RA4.STP RA5.STP RA6.STP RA7.STP RA8.STP RA9.STP RA10.STP U1.3 U1.24 U1.29 U1.33 U1.34 U1.35 U1.36 U1.40 U1.41 U1.42 U1.43 U1.44 U1.45 U1.46 U1.47 U1.48 U1.49 U1.55 U1.56 U1.57 U1.58 U1.59 U1.60 U1.61 U1.62 U1.63 U1.64 U1.68 U1.69 U1.70 U1.71 U1.73 U1.74 U1.75 U1.81 U1.82 U1.83 U1.84 U1.86 U1.87 U1.88 U1.89 U1.93 U1.94 U1.116 U1.139 U1.140 U1.141 U1.145 U1.146 U1.147 U1.148 U1.149 U1.150 U1.151 U1.152 U1.154 U1.192 U1.193 U1.194 U1.198 U1.199 U1.200 U1.201 U1.202 U1.203 U1.204 U1.205 U1.206 U1.FID1 U1.FID2 U2.0 U2.1 U3.4 U4.4 U5.2 U5.9 U5.12 U5.13 U5.14 U5.15 U5.16 U6.1

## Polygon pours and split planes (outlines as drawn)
GND on Bottom Layer "Bottom Layer-GND" (solid, remove dead copper, pour order 1001): 179.995,0 179.995,50.5 -0.005,50.5 -0.005,0
GND on Top Layer "Top Layer-GND" (solid, remove dead copper, pour order 1000): 0,0 0,50.5 180,50.5 180,0

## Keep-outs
Keep-Out Layer:
  circle w0.2: c5.25,5.25 r4
  circle w0.2: c174.75,5.275 r4
  circle w0.2: c5.25,45.25 r4
  circle w0.2: c174.75,45.25 r4
  lines w0.635: 0,0 0,50.5 180,50.5 180,0 0,0

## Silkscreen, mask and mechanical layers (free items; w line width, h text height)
Top Overlay:
  drawing of 3334 lines, arcs and shapes, not listed
  text "SL" at 54.182,46.321 h1.3
  text "REV 1.01" at 59.262,46.321 h1.3
  text "CONTRAST" at 1.9,26.6 h1
  text "PWR" at 179.324,20.574 h1.2 r90
  text "TEST/" at 3.6,11.5 h1
  text "RESET" at 3.4,9.8 h1
  text "7" at 109.6,6.5 h1.2
  text "6" at 112,6.5 h1.2
  text "5" at 114.7,6.5 h1.2
  text "4" at 117.3,6.5 h1.2
  text "3" at 120.1,6.5 h1.2
  text "2" at 122.7,6.5 h1.2
  text "1" at 125.5,6.5 h1.2
  text "0" at 128.1,6.5 h1.2
  text "DONE" at 132.968,0.946 h1.2
Unit PCB Boundary:
  lines w0.2: 0,0 180,0 180,50.5 0,50.5 0,0
Overlay boundary:
  lines w0.2: 0.508,0.508 0.508,50.038 179.5,50.025 179.492,0.508 0.508,0.508
WS Board Travel:
  lines w0.2: 48.555,-2.145 50.8,-4.4 ; 48.9,-14.38 50.8,-14.38 48.9,-12.48 48.9,-11.8 ; 48.9,-10.5 50.8,-12.4 ; 48.9,-8.5 50.8,-10.4 ; 48.9,-6.5 50.8,-8.4 ; 48.9,-4.5 50.8,-6.4
  lines w0.203: 48.9,-14.38 48.9,-4.1 46.6,-4.1 49.9,-0.8 53.2,-4.1 50.8,-4.1 50.8,-14.38
  text "Via Stitching" at 41.5,-17.3 h1.5
Mechanical 15:
  lines w0.2: 0.3,40.7 180,40.7
Sheet Detail:
  drawing of 1882 lines, arcs and shapes, not listed
  text "1" at -27.183,163.091 h1.78
  text "2" at 21.856,163.091 h1.78
  text "3" at 71.115,163.091 h1.78
  text "4" at 120.408,163.091 h1.78
  text "5" at 169.684,163.091 h1.78
  text "6" at 218.706,163.091 h1.78
  text "7" at 268.236,163.091 h1.78
  text "8" at 317.258,163.091 h1.78
  text "A" at -49.315,129.106 h1.78
  text "A" at 339.305,129.106 h1.78
  text "B" at -49.315,58.494 h1.78
  text "B" at 339.305,58.494 h1.78
  text "C" at -49.315,-12.118 h1.78
  text "C" at 339.305,-12.118 h1.78
  text "D" at -49.315,-82.222 h1.78
  text "D" at 339.305,-82.222 h1.78
  text "ENGINEER:" at 224.37,-82.4 h1.14
  text "TITLE:" at 262.47,-82.4 h1.14
  text "PCB Specialist Training" at 271.355,-85.655 h3
  text "PCB DESIGNER:" at 224.37,-89.893 h1.14
  text "Clearance Checking in 3D" at 271.355,-90.735 h3
  text "DATE:" at 224.37,-97.64 h1.14
  text "PART NO.:" at 262.47,-97.64 h1.14
  text "REV:" at 315.81,-97.64 h1.14
  text "Altium Limited" at 191.35,-100.18 h1.78
  text "A" at 324.566,-100.558 h3
  text ".PRINT_DATE" at 225.64,-100.688 h1.78
  text "12a Rodborough Rd" at 191.35,-102.72 h1.78
  text "Frenchs Forest" at 191.35,-105.26 h1.78
  text "FILE NAME:" at 224.37,-105.26 h1.14
  text "DWG NO:" at 262.47,-105.26 h1.14
  text "SCALE:" at 315.81,-105.26 h1.14
  text "NONE" at 323.372,-107.67 h1.52
  text "NSW 2086" at 191.35,-107.8 h1.78
  text ".PCB_FILE_NAME_NO_PATH" at 225.64,-108.308 h1.78
  text "1" at -27.183,-113.769 h1.78
  text "2" at 21.856,-113.769 h1.78
  text "3" at 71.115,-113.769 h1.78
  text "4" at 120.408,-113.769 h1.78
  text "5" at 169.684,-113.769 h1.78
  text "6" at 218.706,-113.769 h1.78
  text "7" at 268.236,-113.769 h1.78
  text "8" at 317.258,-113.769 h1.78
Drill Drawing:
  text ".Legend" at 121,56 h1

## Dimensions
0,-0.005 to 180,-0.005 on Dimensions
0,0 to -0.005,50.5 on Dimensions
